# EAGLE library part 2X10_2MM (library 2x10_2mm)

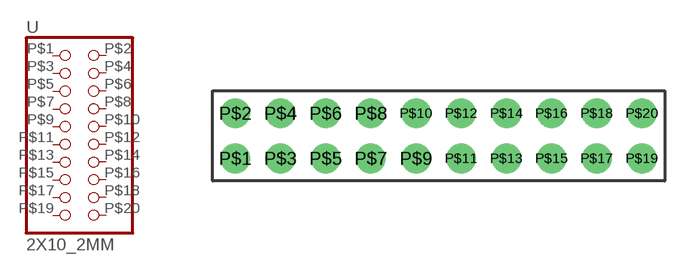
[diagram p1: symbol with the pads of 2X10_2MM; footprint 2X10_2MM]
Designator prefix -

## 2X10_2MM  [2X10_2MM]
P$1  1  pas
P$2  2  pas
P$3  3  pas
P$4  4  pas
P$5  5  pas
P$6  6  pas
P$7  7  pas
P$8  8  pas
P$9  9  pas
P$10  10  pas
P$11  11  pas
P$12  12  pas
P$13  13  pas
P$14  14  pas
P$15  15  pas
P$16  16  pas
P$17  17  pas
P$18  18  pas
P$19  19  pas
P$20  20  pas

## Footprint 2X10_2MM (pad centres in mm)
drill 0.8 round: P$1 -9,3; P$2 -9,5; P$3 -7,3; P$4 -7,5; P$5 -5,3; P$6 -5,5; P$7 -3,3; P$8 -3,5; P$9 -1,3; P$10 -1,5; P$11 1,3; P$12 1,5; P$13 3,3; P$14 3,5; P$15 5,3; P$16 5,5; P$17 7,3; P$18 7,5; P$19 9,3; P$20 9,5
